VERSION 5.8 ;
BUSBITCHARS "[]" ;
DIVIDERCHAR "/" ;
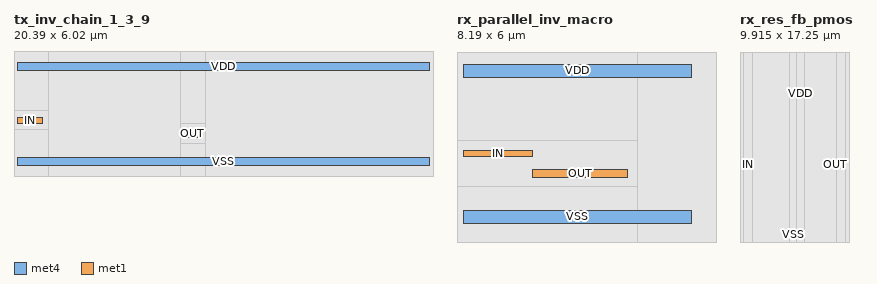
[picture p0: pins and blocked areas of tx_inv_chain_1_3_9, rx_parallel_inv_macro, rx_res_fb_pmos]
MACRO tx_inv_chain_1_3_9
  CLASS BLOCK ;
  ORIGIN 0 0 ;
  FOREIGN tx_inv_chain_1_3_9 0 0 ;
  SIZE 20.390 BY 6.020 ;
  SYMMETRY X Y ;
  PIN VDD
    DIRECTION INOUT ;
    USE POWER ;
    PORT
      LAYER met4 ;
        RECT 0.190 5.110 20.190 5.510 ;
    END
  END VDD
  PIN VSS
    DIRECTION INOUT ;
    USE GROUND ;
    PORT
      LAYER met4 ;
        RECT 0.190 0.510 20.190 0.910 ;
    END
  END VSS
  PIN IN
    DIRECTION INPUT ;
    USE SIGNAL ;
    PORT
      LAYER met1 ;
        RECT 0.190 2.560 1.390 2.860 ;
    END
  END IN
  PIN OUT
    DIRECTION OUTPUT ;
    USE SIGNAL ;
    PORT
      LAYER met1 ;
        RECT 8.390 1.860 8.990 2.260 ;
    END
  END OUT
  OBS
    LAYER met2 ;
      RECT 0.000 0.000 20.390 6.020 ;
    LAYER met3 ;
      RECT 0.000 0.000 20.390 6.020 ;
    LAYER met5 ;
      RECT 0.000 0.000 20.390 6.020 ;
    LAYER met1 ;
      RECT 0.000 0.000 1.690 2.260 ;
    LAYER met1 ;
      RECT 0.000 3.160 1.690 6.020 ;
    LAYER met1 ;
      RECT 1.690 0.000 8.090 6.020 ;
    LAYER met1 ;
      RECT 8.090 0.000 9.290 1.560 ;
    LAYER met1 ;
      RECT 8.090 2.560 9.290 6.020 ;
    LAYER met1 ;
      RECT 9.290 0.000 20.390 6.020 ;
  END
END tx_inv_chain_1_3_9
MACRO rx_parallel_inv_macro
  CLASS BLOCK ;
  ORIGIN 0 0 ;
  FOREIGN rx_parallel_inv_macro 0 0 ;
  SIZE 8.190 BY 6.000 ;
  SYMMETRY X Y ;
  PIN VDD
    DIRECTION INOUT ;
    USE POWER ;
    PORT
      LAYER met4 ;
        RECT 0.190 5.200 7.390 5.600 ;
    END
  END VDD
  PIN VSS
    DIRECTION INOUT ;
    USE GROUND ;
    PORT
      LAYER met4 ;
        RECT 0.190 0.600 7.390 1.000 ;
    END
  END VSS
  PIN IN
    DIRECTION INPUT ;
    USE SIGNAL ;
    PORT
      LAYER met1 ;
        RECT 0.190 2.700 2.390 2.900 ;
    END
  END IN
  PIN OUT
    DIRECTION OUTPUT ;
    USE SIGNAL ;
    PORT
      LAYER met1 ;
        RECT 2.390 2.050 5.390 2.300 ;
    END
  END OUT
  OBS
    LAYER met2 ;
      RECT 0.000 0.000 8.190 6.000 ;
    LAYER met3 ;
      RECT 0.000 0.000 8.190 6.000 ;
    LAYER met5 ;
      RECT 0.000 0.000 8.190 6.000 ;
    LAYER met1 ;
      RECT 0.000 0.000 5.690 1.750 ;
    LAYER met1 ;
      RECT 0.000 3.200 5.690 6.000 ;
    LAYER met1 ;
      RECT 5.690 0.000 8.190 6.000 ;
  END
END rx_parallel_inv_macro
MACRO rx_res_fb_pmos
  CLASS BLOCK ;
  ORIGIN 0 0 ;
  FOREIGN rx_res_fb_pmos 0 0 ;
  SIZE 9.915 BY 17.250 ;
  SYMMETRY X Y ;
  PIN VDD
    DIRECTION INOUT ;
    USE POWER ;
    PORT
      LAYER met1 ;
        RECT 5.415 13.360 5.590 13.555 ;
    END
  END VDD
  PIN VSS
    DIRECTION INOUT ;
    USE GROUND ;
    PORT
      LAYER met1 ;
        RECT 4.755 0.620 4.930 0.815 ;
    END
  END VSS
  PIN IN
    DIRECTION INPUT ;
    USE SIGNAL ;
    PORT
      LAYER met1 ;
        RECT 0.645 6.945 0.830 7.135 ;
    END
  END IN
  PIN OUT
    DIRECTION OUTPUT ;
    USE SIGNAL ;
    PORT
      LAYER met1 ;
        RECT 9.055 6.975 9.245 7.115 ;
    END
  END OUT
  OBS
    LAYER met2 ;
      RECT 0.000 0.000 9.915 17.250 ;
    LAYER met3 ;
      RECT 0.000 0.000 9.915 17.250 ;
    LAYER met4 ;
      RECT 0.000 0.000 9.915 17.250 ;
    LAYER met5 ;
      RECT 0.000 0.000 9.915 17.250 ;
    LAYER met1 ;
      RECT 0.000 0.000 0.345 17.250 ;
    LAYER met1 ;
      RECT 0.345 0.000 1.130 6.645 ;
    LAYER met1 ;
      RECT 0.345 7.435 1.130 17.250 ;
    LAYER met1 ;
      RECT 1.130 0.000 4.455 17.250 ;
    LAYER met1 ;
      RECT 4.455 0.000 5.230 0.320 ;
    LAYER met1 ;
      RECT 4.455 1.115 5.230 17.250 ;
    LAYER met1 ;
      RECT 5.115 0.000 5.890 13.060 ;
    LAYER met1 ;
      RECT 5.115 13.855 5.890 17.250 ;
    LAYER met1 ;
      RECT 5.890 0.000 8.755 17.250 ;
    LAYER met1 ;
      RECT 8.755 0.000 9.545 6.675 ;
    LAYER met1 ;
      RECT 8.755 7.415 9.545 17.250 ;
    LAYER met1 ;
      RECT 9.545 0.000 9.915 17.250 ;
  END
END rx_res_fb_pmos
END LIBRARY
